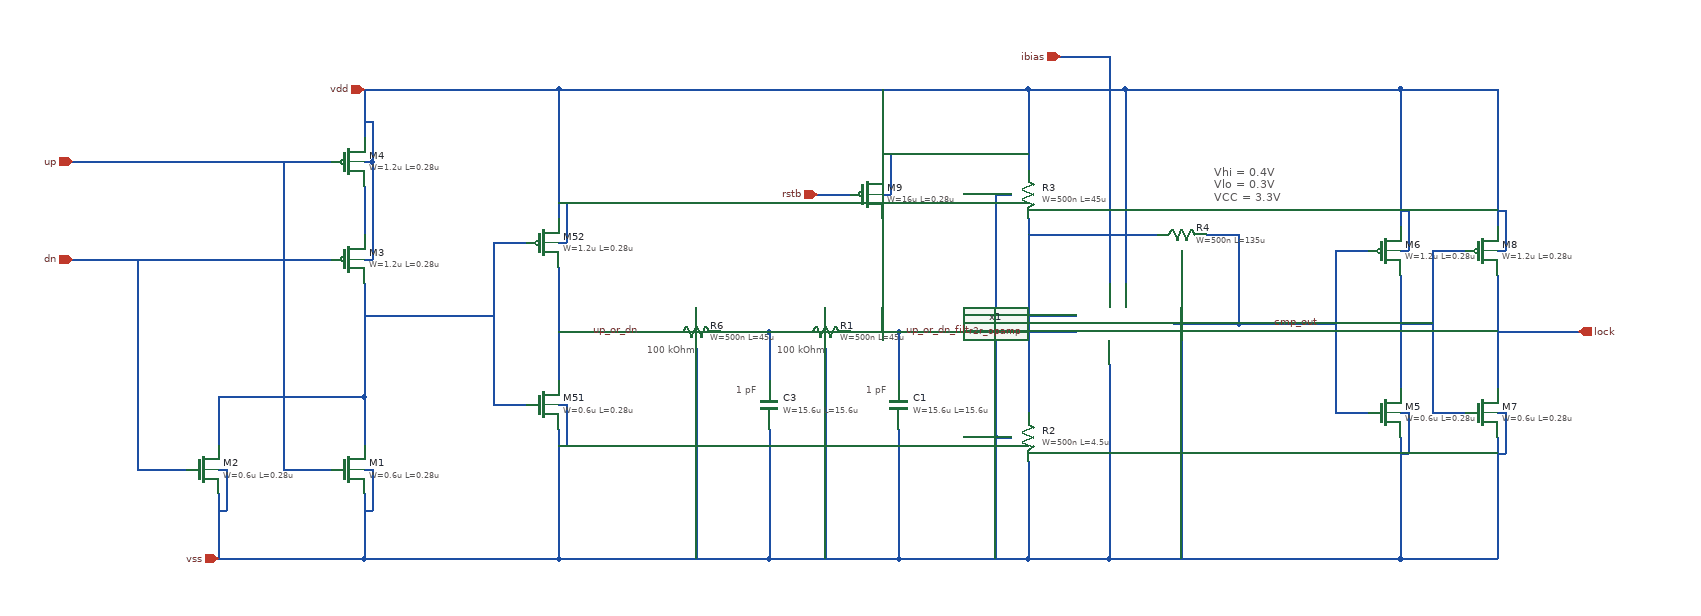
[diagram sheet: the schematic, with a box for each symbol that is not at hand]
v {xschem version=3.4.5 file_version=1.2
}
G {}
K {}
V {}
S {}
E {}
T {Vhi = 0.4V
Vlo = 0.3V
VCC = 3.3V} 1650 -550 0 0 0.4 0.4 {}
T {1 pF} 1060 -280 0 0 0.2 0.2 {}
T {1 pF} 1220 -280 0 0 0.2 0.2 {}
T {100 kOhm} 950 -330 0 0 0.2 0.2 {}
T {100 kOhm} 1110 -330 0 0 0.2 0.2 {}
N 760 -250 800 -250 {
lab=#net1}
N 760 -450 760 -250 {
lab=#net1}
N 760 -450 800 -450 {
lab=#net1}
N 720 -360 760 -360 {
lab=#net1}
N 840 -520 840 -480 {
lab=vdd}
N 840 -450 850 -450 {
lab=vdd}
N 850 -500 850 -450 {
lab=vdd}
N 840 -500 850 -500 {
lab=vdd}
N 840 -220 840 -180 {
lab=vss}
N 840 -250 850 -250 {
lab=vss}
N 850 -250 850 -200 {
lab=vss}
N 840 -200 850 -200 {
lab=vss}
N 840 -420 840 -280 {
lab=up_or_dn}
N 840 -640 840 -520 {
lab=vdd}
N 840 -180 840 -60 {
lab=vss}
N 840 -340 940 -340 {
lab=up_or_dn}
N 420 -140 420 -60 {
lab=vss}
N 600 -140 600 -60 {
lab=vss}
N 600 -170 610 -170 {
lab=vss}
N 610 -170 610 -120 {
lab=vss}
N 600 -120 610 -120 {
lab=vss}
N 420 -170 430 -170 {
lab=vss}
N 430 -170 430 -120 {
lab=vss}
N 420 -120 430 -120 {
lab=vss}
N 320 -170 380 -170 {
lab=dn}
N 500 -170 560 -170 {
lab=up}
N 420 -260 420 -200 {
lab=#net1}
N 420 -260 600 -260 {
lab=#net1}
N 600 -260 600 -200 {
lab=#net1}
N 600 -640 600 -580 {
lab=vdd}
N 600 -550 610 -550 {
lab=vdd}
N 610 -600 610 -550 {
lab=vdd}
N 600 -600 610 -600 {
lab=vdd}
N 600 -520 600 -460 {
lab=#net2}
N 600 -430 610 -430 {
lab=vdd}
N 610 -550 610 -430 {
lab=vdd}
N 600 -400 600 -260 {
lab=#net1}
N 600 -360 720 -360 {
lab=#net1}
N 340 -430 560 -430 {
lab=dn}
N 340 -550 560 -550 {
lab=up}
N 600 -640 840 -640 {
lab=vdd}
N 420 -60 600 -60 {
lab=vss}
N 600 -60 840 -60 {
lab=vss}
N 240 -430 340 -430 {
lab=dn}
N 240 -550 340 -550 {
lab=up}
N 320 -430 320 -170 {
lab=dn}
N 500 -550 500 -170 {
lab=up}
N 940 -340 980 -340 {
lab=up_or_dn}
N 1040 -340 1100 -340 {
lab=#net3}
N 1100 -340 1100 -280 {
lab=#net3}
N 1100 -220 1100 -60 {
lab=vss}
N 840 -60 1100 -60 {
lab=vss}
N 1100 -340 1140 -340 {
lab=#net3}
N 1200 -340 1260 -340 {
lab=up_or_dn_filt}
N 1260 -340 1260 -280 {
lab=up_or_dn_filt}
N 1260 -220 1260 -60 {
lab=vss}
N 1100 -60 1260 -60 {
lab=vss}
N 1260 -340 1440 -340 {
lab=up_or_dn_filt}
N 1440 -340 1480 -340 {
lab=up_or_dn_filt}
N 1420 -180 1420 -60 {
lab=vss}
N 1260 -60 1420 -60 {
lab=vss}
N 1420 -360 1420 -240 {
lab=#net4}
N 1420 -360 1480 -360 {
lab=#net4}
N 840 -640 1420 -640 {
lab=vdd}
N 1540 -640 1540 -400 {
lab=vdd}
N 1420 -640 1540 -640 {
lab=vdd}
N 1420 -480 1420 -360 {
lab=#net4}
N 1420 -640 1420 -540 {
lab=vdd}
N 1420 -460 1580 -460 {
lab=#net4}
N 1640 -460 1680 -460 {
lab=cmp_out}
N 1680 -460 1680 -350 {
lab=cmp_out}
N 1600 -350 1680 -350 {
lab=cmp_out}
N 1680 -350 1760 -350 {
lab=cmp_out}
N 1520 -300 1520 -60 {
lab=vss}
N 1420 -60 1520 -60 {
lab=vss}
N 1800 -240 1840 -240 {
lab=cmp_out}
N 1800 -440 1800 -240 {
lab=cmp_out}
N 1800 -440 1840 -440 {
lab=cmp_out}
N 1760 -350 1800 -350 {
lab=cmp_out}
N 1880 -510 1880 -470 {
lab=vdd}
N 1880 -440 1890 -440 {
lab=vdd}
N 1890 -490 1890 -440 {
lab=vdd}
N 1880 -490 1890 -490 {
lab=vdd}
N 1880 -210 1880 -170 {
lab=vss}
N 1880 -240 1890 -240 {
lab=vss}
N 1890 -240 1890 -190 {
lab=vss}
N 1880 -190 1890 -190 {
lab=vss}
N 1880 -410 1880 -270 {
lab=#net5}
N 1880 -630 1880 -510 {
lab=vdd}
N 2000 -340 2100 -340 {
lab=lock}
N 1540 -640 1880 -640 {
lab=vdd}
N 1880 -640 1880 -630 {
lab=vdd}
N 1520 -60 1880 -60 {
lab=vss}
N 1880 -170 1880 -60 {
lab=vss}
N 1520 -440 1520 -400 {
lab=ibias}
N 1520 -680 1520 -440 {
lab=ibias}
N 1460 -680 1520 -680 {
lab=ibias}
N 1920 -240 1960 -240 {
lab=#net5}
N 1920 -440 1920 -240 {
lab=#net5}
N 1920 -440 1960 -440 {
lab=#net5}
N 1880 -350 1920 -350 {
lab=#net5}
N 2000 -510 2000 -470 {
lab=vdd}
N 2000 -440 2010 -440 {
lab=vdd}
N 2010 -490 2010 -440 {
lab=vdd}
N 2000 -490 2010 -490 {
lab=vdd}
N 2000 -210 2000 -170 {
lab=vss}
N 2000 -240 2010 -240 {
lab=vss}
N 2010 -240 2010 -190 {
lab=vss}
N 2000 -190 2010 -190 {
lab=vss}
N 2000 -410 2000 -270 {
lab=lock}
N 2000 -630 2000 -510 {
lab=vdd}
N 2000 -170 2000 -60 {
lab=vss}
N 2000 -640 2000 -630 {
lab=vdd}
N 1880 -640 2000 -640 {
lab=vdd}
N 1880 -60 2000 -60 {
lab=vss}
N 1160 -510 1200 -510 {
lab=rstb}
N 1240 -580 1240 -540 {
lab=vdd}
N 1240 -510 1250 -510 {
lab=vdd}
N 1250 -560 1250 -510 {
lab=vdd}
N 1240 -560 1250 -560 {
lab=vdd}
N 1240 -480 1240 -340 {
lab=up_or_dn_filt}
N 1240 -640 1240 -580 {
lab=vdd}
N 1010 -320 1010 -60 {
lab=vss}
N 1170 -320 1170 -60 {
lab=vss}
N 1380 -210 1400 -210 {
lab=vss}
N 1380 -210 1380 -60 {
lab=vss}
N 1380 -510 1400 -510 {
lab=vss}
N 1380 -510 1380 -210 {
lab=vss}
N 1610 -440 1610 -60 {
lab=vss}
C {symbols/nfet_03v3.sym} 820 -250 0 0 {name=M51
L=0.28u
W=0.6u
nf=1
m=1
ad="'int((nf+1)/2) * W/nf * 0.18u'"
pd="'2*int((nf+1)/2) * (W/nf + 0.18u)'"
as="'int((nf+2)/2) * W/nf * 0.18u'"
ps="'2*int((nf+2)/2) * (W/nf + 0.18u)'"
nrd="'0.18u / W'" nrs="'0.18u / W'"
sa=0 sb=0 sd=0
model=nfet_03v3
spiceprefix=X
}
C {symbols/pfet_03v3.sym} 820 -450 0 0 {name=M52
L=0.28u
W=1.2u
nf=1
m=1
ad="'int((nf+1)/2) * W/nf * 0.18u'"
pd="'2*int((nf+1)/2) * (W/nf + 0.18u)'"
as="'int((nf+2)/2) * W/nf * 0.18u'"
ps="'2*int((nf+2)/2) * (W/nf + 0.18u)'"
nrd="'0.18u / W'" nrs="'0.18u / W'"
sa=0 sb=0 sd=0
model=pfet_03v3
spiceprefix=X
}
C {symbols/nfet_03v3.sym} 580 -170 0 0 {name=M1
L=0.28u
W=0.6u
nf=1
m=1
ad="'int((nf+1)/2) * W/nf * 0.18u'"
pd="'2*int((nf+1)/2) * (W/nf + 0.18u)'"
as="'int((nf+2)/2) * W/nf * 0.18u'"
ps="'2*int((nf+2)/2) * (W/nf + 0.18u)'"
nrd="'0.18u / W'" nrs="'0.18u / W'"
sa=0 sb=0 sd=0
model=nfet_03v3
spiceprefix=X
}
C {symbols/nfet_03v3.sym} 400 -170 0 0 {name=M2
L=0.28u
W=0.6u
nf=1
m=1
ad="'int((nf+1)/2) * W/nf * 0.18u'"
pd="'2*int((nf+1)/2) * (W/nf + 0.18u)'"
as="'int((nf+2)/2) * W/nf * 0.18u'"
ps="'2*int((nf+2)/2) * (W/nf + 0.18u)'"
nrd="'0.18u / W'" nrs="'0.18u / W'"
sa=0 sb=0 sd=0
model=nfet_03v3
spiceprefix=X
}
C {symbols/pfet_03v3.sym} 580 -430 0 0 {name=M3
L=0.28u
W=1.2u
nf=1
m=1
ad="'int((nf+1)/2) * W/nf * 0.18u'"
pd="'2*int((nf+1)/2) * (W/nf + 0.18u)'"
as="'int((nf+2)/2) * W/nf * 0.18u'"
ps="'2*int((nf+2)/2) * (W/nf + 0.18u)'"
nrd="'0.18u / W'" nrs="'0.18u / W'"
sa=0 sb=0 sd=0
model=pfet_03v3
spiceprefix=X
}
C {symbols/pfet_03v3.sym} 580 -550 0 0 {name=M4
L=0.28u
W=1.2u
nf=1
m=1
ad="'int((nf+1)/2) * W/nf * 0.18u'"
pd="'2*int((nf+1)/2) * (W/nf + 0.18u)'"
as="'int((nf+2)/2) * W/nf * 0.18u'"
ps="'2*int((nf+2)/2) * (W/nf + 0.18u)'"
nrd="'0.18u / W'" nrs="'0.18u / W'"
sa=0 sb=0 sd=0
model=pfet_03v3
spiceprefix=X
}
C {r2r_opamp.sym} 1480 -300 0 0 {name=x1}
C {symbols/nfet_03v3.sym} 1860 -240 0 0 {name=M5
L=0.28u
W=0.6u
nf=1
m=1
ad="'int((nf+1)/2) * W/nf * 0.18u'"
pd="'2*int((nf+1)/2) * (W/nf + 0.18u)'"
as="'int((nf+2)/2) * W/nf * 0.18u'"
ps="'2*int((nf+2)/2) * (W/nf + 0.18u)'"
nrd="'0.18u / W'" nrs="'0.18u / W'"
sa=0 sb=0 sd=0
model=nfet_03v3
spiceprefix=X
}
C {symbols/pfet_03v3.sym} 1860 -440 0 0 {name=M6
L=0.28u
W=1.2u
nf=1
m=1
ad="'int((nf+1)/2) * W/nf * 0.18u'"
pd="'2*int((nf+1)/2) * (W/nf + 0.18u)'"
as="'int((nf+2)/2) * W/nf * 0.18u'"
ps="'2*int((nf+2)/2) * (W/nf + 0.18u)'"
nrd="'0.18u / W'" nrs="'0.18u / W'"
sa=0 sb=0 sd=0
model=pfet_03v3
spiceprefix=X
}
C {ipin.sym} 240 -550 0 0 {name=p1 lab=up}
C {ipin.sym} 240 -430 0 0 {name=p2 lab=dn}
C {ipin.sym} 600 -640 0 0 {name=p3 lab=vdd}
C {ipin.sym} 420 -60 0 0 {name=p4 lab=vss}
C {ipin.sym} 1460 -680 0 0 {name=p5 lab=ibias}
C {opin.sym} 2100 -340 0 0 {name=p6 lab=lock}
C {lab_wire.sym} 940 -340 0 0 {name=p7 sig_type=std_logic lab=up_or_dn}
C {lab_wire.sym} 1350 -340 0 0 {name=p8 sig_type=std_logic lab=up_or_dn_filt}
C {lab_wire.sym} 1780 -350 0 0 {name=p9 sig_type=std_logic lab=cmp_out}
C {symbols/nfet_03v3.sym} 1980 -240 0 0 {name=M7
L=0.28u
W=0.6u
nf=1
m=1
ad="'int((nf+1)/2) * W/nf * 0.18u'"
pd="'2*int((nf+1)/2) * (W/nf + 0.18u)'"
as="'int((nf+2)/2) * W/nf * 0.18u'"
ps="'2*int((nf+2)/2) * (W/nf + 0.18u)'"
nrd="'0.18u / W'" nrs="'0.18u / W'"
sa=0 sb=0 sd=0
model=nfet_03v3
spiceprefix=X
}
C {symbols/pfet_03v3.sym} 1980 -440 0 0 {name=M8
L=0.28u
W=1.2u
nf=1
m=1
ad="'int((nf+1)/2) * W/nf * 0.18u'"
pd="'2*int((nf+1)/2) * (W/nf + 0.18u)'"
as="'int((nf+2)/2) * W/nf * 0.18u'"
ps="'2*int((nf+2)/2) * (W/nf + 0.18u)'"
nrd="'0.18u / W'" nrs="'0.18u / W'"
sa=0 sb=0 sd=0
model=pfet_03v3
spiceprefix=X
}
C {symbols/pfet_03v3.sym} 1220 -510 0 0 {name=M9
L=0.28u
W=16u
nf=1
m=1
ad="'int((nf+1)/2) * W/nf * 0.18u'"
pd="'2*int((nf+1)/2) * (W/nf + 0.18u)'"
as="'int((nf+2)/2) * W/nf * 0.18u'"
ps="'2*int((nf+2)/2) * (W/nf + 0.18u)'"
nrd="'0.18u / W'" nrs="'0.18u / W'"
sa=0 sb=0 sd=0
model=pfet_03v3
spiceprefix=X
}
C {ipin.sym} 1160 -510 0 0 {name=p10 lab=rstb}
C {symbols/cap_mim_2f0fF.sym} 1100 -250 0 0 {name=C3
W=15.6u
L=15.6u
model=cap_mim_2f0fF
spiceprefix=X
m=2}
C {symbols/cap_mim_2f0fF.sym} 1260 -250 0 0 {name=C1
W=15.6u
L=15.6u
model=cap_mim_2f0fF
spiceprefix=X
m=2}
C {gf180mcu_fd_pr/ppolyf_u_1k.sym} 1010 -340 3 0 {name=R6
W=500n
L=45u
model=ppolyf_u_1k
spiceprefix=X
m=1}
C {gf180mcu_fd_pr/ppolyf_u_1k.sym} 1170 -340 3 0 {name=R1
W=500n
L=45u
model=ppolyf_u_1k
spiceprefix=X
m=1}
C {gf180mcu_fd_pr/ppolyf_u_1k.sym} 1420 -210 0 0 {name=R2
W=500n
L=4.5u
model=ppolyf_u_1k
spiceprefix=X
m=1}
C {gf180mcu_fd_pr/ppolyf_u_1k.sym} 1420 -510 0 0 {name=R3
W=500n
L=45u
model=ppolyf_u_1k
spiceprefix=X
m=1}
C {gf180mcu_fd_pr/ppolyf_u_1k.sym} 1610 -460 3 0 {name=R4
W=500n
L=135u
model=ppolyf_u_1k
spiceprefix=X
m=1}
